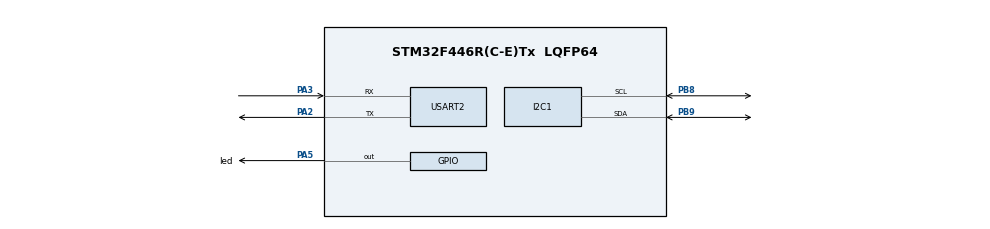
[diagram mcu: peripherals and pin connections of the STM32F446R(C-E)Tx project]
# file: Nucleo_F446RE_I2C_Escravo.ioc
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Mcu.Family=STM32F4
Mcu.Name=STM32F446R(C-E)Tx
Mcu.Package=LQFP64
NVIC.PriorityGroup=NVIC_PRIORITYGROUP_0
PA2.Mode=Asynchronous
PA2.Signal=USART2_TX
PA3.Mode=Asynchronous
PA3.Signal=USART2_RX
PA5.GPIO_Label=led
PA5.Signal=GPIO_Output
PB8.GPIO_Pu=GPIO_PULLUP
PB8.Mode=I2C
PB8.Signal=I2C1_SCL
PB9.GPIO_Pu=GPIO_PULLUP
PB9.Mode=I2C
PB9.Signal=I2C1_SDA
ProjectManager.HeapSize=0x200
ProjectManager.StackSize=0x400
ProjectManager.TargetToolchain=STM32CubeIDE
RCC.48MHZClocksFreq_Value=84000000
RCC.AHBFreq_Value=84000000
RCC.APB1CLKDivider=RCC_HCLK_DIV2
RCC.APB1Freq_Value=42000000
RCC.APB1TimFreq_Value=84000000
RCC.APB2Freq_Value=84000000
RCC.APB2TimFreq_Value=84000000
RCC.CortexFreq_Value=84000000
RCC.FLatency-AdvancedSettings=FLASH_LATENCY_2
RCC.HCLKFreq_Value=84000000
RCC.HSE_VALUE=8000000
RCC.HSI_VALUE=16000000
RCC.PLLN=336
RCC.PLLP=RCC_PLLP_DIV4
RCC.SYSCLKFreq_VALUE=84000000
RCC.SYSCLKSource=RCC_SYSCLKSOURCE_PLLCLK
RCC.USBFreq_Value=168000000
RCC.VCOOutputFreq_Value=336000000
USART2.VirtualMode=VM_ASYNC
board=NUCLEO-F446RE

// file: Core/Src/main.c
/* USER CODE BEGIN Header */
/**
  ******************************************************************************
  * @file           : main.c
  * @brief          : Main program body
  ******************************************************************************
  * @attention
  *
  * Copyright (c) 2025 STMicroelectronics.
  * All rights reserved.
  *
  * This software is licensed under terms that can be found in the LICENSE file
  * in the root directory of this software component.
  * If no LICENSE file comes with this software, it is provided AS-IS.
  *
  ******************************************************************************
  */
/* USER CODE END Header */
#include "main.h"

/* USER CODE BEGIN Includes */
#include <string.h>
/* USER CODE END Includes */

I2C_HandleTypeDef hi2c1;

UART_HandleTypeDef huart2;

/* USER CODE BEGIN PV */
uint8_t i2c_rx_buffer[1];  // Apenas 1 byte esperado
/* USER CODE END PV */

void SystemClock_Config(void);
static void MX_GPIO_Init(void);
static void MX_I2C1_Init(void);
static void MX_USART2_UART_Init(void);

int main(void)
{

  /* MCU Configuration--------------------------------------------------------*/

  /* Reset of all peripherals, Initializes the Flash interface and the Systick. */
  HAL_Init();

  /* Configure the system clock */
  SystemClock_Config();

  /* Initialize all configured peripherals */
  MX_GPIO_Init();
  MX_I2C1_Init();
  MX_USART2_UART_Init();
  /* USER CODE BEGIN 2 */
  HAL_GPIO_WritePin(led_GPIO_Port, led_Pin, GPIO_PIN_RESET);
  /* USER CODE END 2 */

  /* Infinite loop */
  /* USER CODE BEGIN WHILE */
  while (1)
  {
	    // Espera o master enviar 1 byte
	    if (HAL_I2C_Slave_Receive(&hi2c1, i2c_rx_buffer, 1, HAL_MAX_DELAY) == HAL_OK)
	    {
	      char comando = i2c_rx_buffer[0];

	      // Liga ou desliga o LED
	      if (comando == '1') {
	        HAL_GPIO_WritePin(GPIOA, GPIO_PIN_5, GPIO_PIN_SET);  // Liga LED
	      } else if (comando == '0') {
	        HAL_GPIO_WritePin(GPIOA, GPIO_PIN_5, GPIO_PIN_RESET);  // Desliga LED
	      }
	    }

    /* USER CODE END WHILE */

  }
}

void SystemClock_Config(void)
{
  RCC_OscInitTypeDef RCC_OscInitStruct = {0};
  RCC_ClkInitTypeDef RCC_ClkInitStruct = {0};

  /** Configure the main internal regulator output voltage
  */
  __HAL_RCC_PWR_CLK_ENABLE();
  __HAL_PWR_VOLTAGESCALING_CONFIG(PWR_REGULATOR_VOLTAGE_SCALE3);

  /** Initializes the RCC Oscillators according to the specified parameters
  * in the RCC_OscInitTypeDef structure.
  */
  RCC_OscInitStruct.OscillatorType = RCC_OSCILLATORTYPE_HSI;
  RCC_OscInitStruct.HSIState = RCC_HSI_ON;
  RCC_OscInitStruct.HSICalibrationValue = RCC_HSICALIBRATION_DEFAULT;
  RCC_OscInitStruct.PLL.PLLState = RCC_PLL_NONE;
  if (HAL_RCC_OscConfig(&RCC_OscInitStruct) != HAL_OK)
  {
    Error_Handler();
  }

  /** Initializes the CPU, AHB and APB buses clocks
  */
  RCC_ClkInitStruct.ClockType = RCC_CLOCKTYPE_HCLK|RCC_CLOCKTYPE_SYSCLK
                              |RCC_CLOCKTYPE_PCLK1|RCC_CLOCKTYPE_PCLK2;
  RCC_ClkInitStruct.SYSCLKSource = RCC_SYSCLKSOURCE_HSI;
  RCC_ClkInitStruct.AHBCLKDivider = RCC_SYSCLK_DIV1;
  RCC_ClkInitStruct.APB1CLKDivider = RCC_HCLK_DIV2;
  RCC_ClkInitStruct.APB2CLKDivider = RCC_HCLK_DIV1;

  if (HAL_RCC_ClockConfig(&RCC_ClkInitStruct, FLASH_LATENCY_0) != HAL_OK)
  {
    Error_Handler();
  }
}

static void MX_I2C1_Init(void)
{

  hi2c1.Instance = I2C1;
  hi2c1.Init.ClockSpeed = 100000;
  hi2c1.Init.DutyCycle = I2C_DUTYCYCLE_2;
  hi2c1.Init.OwnAddress1 = 84;
  hi2c1.Init.AddressingMode = I2C_ADDRESSINGMODE_7BIT;
  hi2c1.Init.DualAddressMode = I2C_DUALADDRESS_DISABLE;
  hi2c1.Init.OwnAddress2 = 0;
  hi2c1.Init.GeneralCallMode = I2C_GENERALCALL_DISABLE;
  hi2c1.Init.NoStretchMode = I2C_NOSTRETCH_DISABLE;
  if (HAL_I2C_Init(&hi2c1) != HAL_OK)
  {
    Error_Handler();
  }

}

static void MX_USART2_UART_Init(void)
{

  huart2.Instance = USART2;
  huart2.Init.BaudRate = 9600;
  huart2.Init.WordLength = UART_WORDLENGTH_8B;
  huart2.Init.StopBits = UART_STOPBITS_1;
  huart2.Init.Parity = UART_PARITY_NONE;
  huart2.Init.Mode = UART_MODE_TX_RX;
  huart2.Init.HwFlowCtl = UART_HWCONTROL_NONE;
  huart2.Init.OverSampling = UART_OVERSAMPLING_16;
  if (HAL_UART_Init(&huart2) != HAL_OK)
  {
    Error_Handler();
  }

}

static void MX_GPIO_Init(void)
{
  GPIO_InitTypeDef GPIO_InitStruct = {0};

  /* GPIO Ports Clock Enable */
  __HAL_RCC_GPIOA_CLK_ENABLE();
  __HAL_RCC_GPIOB_CLK_ENABLE();

  /*Configure GPIO pin Output Level */
  HAL_GPIO_WritePin(led_GPIO_Port, led_Pin, GPIO_PIN_RESET);

  /*Configure GPIO pin : led_Pin */
  GPIO_InitStruct.Pin = led_Pin;
  GPIO_InitStruct.Mode = GPIO_MODE_OUTPUT_PP;
  GPIO_InitStruct.Pull = GPIO_NOPULL;
  GPIO_InitStruct.Speed = GPIO_SPEED_FREQ_LOW;
  HAL_GPIO_Init(led_GPIO_Port, &GPIO_InitStruct);

}

void Error_Handler(void)
{
  __disable_irq();
  while (1)
  {
  }
}
